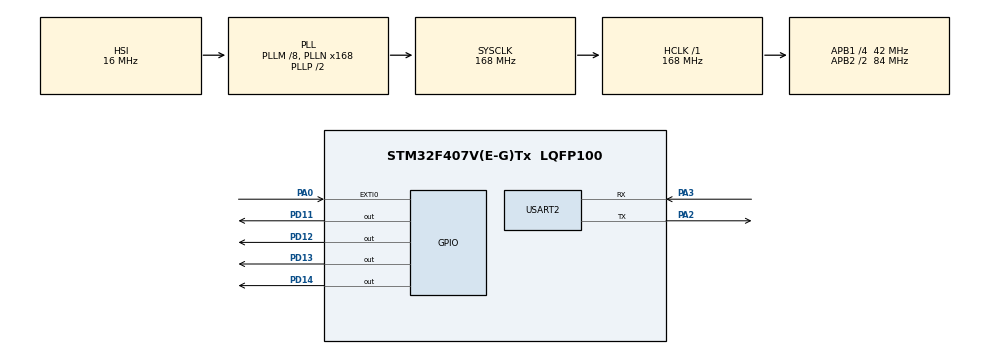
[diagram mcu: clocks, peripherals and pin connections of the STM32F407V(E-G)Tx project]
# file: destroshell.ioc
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Mcu.Family=STM32F4
Mcu.Name=STM32F407V(E-G)Tx
Mcu.Package=LQFP100
NVIC.EXTI0_IRQn=true\:6\:0\:true\:false\:true\:true\:false\:true
NVIC.PriorityGroup=NVIC_PRIORITYGROUP_4
NVIC.TIM6_DAC_IRQn=true\:15\:0\:false\:false\:true\:false\:true\:true
NVIC.TimeBase=TIM6_DAC_IRQn
NVIC.TimeBaseIP=TIM6
NVIC.USART2_IRQn=true\:5\:0\:true\:false\:true\:true\:false\:true
PA0-WKUP.Signal=GPXTI0
PA2.Mode=Asynchronous
PA2.Signal=USART2_TX
PA3.Mode=Asynchronous
PA3.Signal=USART2_RX
PD11.GPIO_Speed=GPIO_SPEED_FREQ_HIGH
PD11.Signal=GPIO_Output
PD12.GPIO_Speed=GPIO_SPEED_FREQ_HIGH
PD12.Signal=GPIO_Output
PD13.GPIO_Speed=GPIO_SPEED_FREQ_HIGH
PD13.Signal=GPIO_Output
PD14.GPIO_Speed=GPIO_SPEED_FREQ_HIGH
PD14.Signal=GPIO_Output
ProjectManager.HeapSize=0x200
ProjectManager.StackSize=0x400
ProjectManager.TargetToolchain=STM32CubeIDE
RCC.48MHZClocksFreq_Value=84000000
RCC.AHBFreq_Value=168000000
RCC.APB1CLKDivider=RCC_HCLK_DIV4
RCC.APB1Freq_Value=42000000
RCC.APB1TimFreq_Value=84000000
RCC.APB2CLKDivider=RCC_HCLK_DIV2
RCC.APB2Freq_Value=84000000
RCC.APB2TimFreq_Value=168000000
RCC.CortexFreq_Value=168000000
RCC.HCLKFreq_Value=168000000
RCC.HSE_VALUE=25000000
RCC.HSI_VALUE=16000000
RCC.LSE_VALUE=32768
RCC.PLLM=8
RCC.PLLN=168
RCC.SYSCLKFreq_VALUE=168000000
RCC.SYSCLKSource=RCC_SYSCLKSOURCE_PLLCLK
RCC.VCOOutputFreq_Value=336000000
USART2.VirtualMode=VM_ASYNC
VP_SYS_VS_tim6.Mode=TIM6
board=custom

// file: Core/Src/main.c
/* USER CODE BEGIN Header */
/**
  ******************************************************************************
  * @file           : main.c
  * @brief          : Main program body
  ******************************************************************************
  * @attention
  *
  * Copyright (c) 2024 STMicroelectronics.
  * All rights reserved.
  *
  * This software is licensed under terms that can be found in the LICENSE file
  * in the root directory of this software component.
  * If no LICENSE file comes with this software, it is provided AS-IS.
  *
  ******************************************************************************
  */
/* USER CODE END Header */
#include "main.h"

/* USER CODE BEGIN Includes */
#include <FreeRTOS.h>
#include <task.h>
#include <queue.h>
/* USER CODE END Includes */

/* USER CODE BEGIN PD */
#define DWT_CTRL    (*(volatile uint32_t*)0xE0001000)
/* USER CODE END PD */

UART_HandleTypeDef shellUSART;

/* USER CODE BEGIN PV */
Shell_Handle_t shellHandle;
/* USER CODE END PV */

void SystemClock_Config(void);
static void MX_GPIO_Init(void);
static void MX_USART2_UART_Init(void);

int main(void)
{

  /* MCU Configuration--------------------------------------------------------*/

  /* Reset of all peripherals, Initializes the Flash interface and the Systick. */
  HAL_Init();

  /* Configure the system clock */
  SystemClock_Config();

  /* Initialize all configured peripherals */
  MX_GPIO_Init();
  MX_USART2_UART_Init();
  /* USER CODE BEGIN 2 */

  //CYCLCNT enable
  DWT_CTRL |= ( 1 << 0);

  SEGGER_SYSVIEW_Conf();

  /* Initialize shell */
  Shell_Init(&shellHandle, &shellUSART);

  /* Create shell task */
  xTaskCreate(Shell_Task, "Shell", 512, &shellHandle, 1, NULL);
  xTaskCreate(vUartTask, "UART", 512, &shellHandle, 1, NULL);

  Shell_RegisterCommand("clear", "Clear the terminal screen", "clear", shell_cmd_clear);
  Shell_RegisterCommand("help", "Display help information for commands", "help [command]", shell_cmd_help);
  Shell_RegisterCommand("status", "Show system status information", "status", shell_cmd_status);
  Shell_RegisterCommand("reset", "Reset the system", "reset", shell_cmd_reset);
  Shell_RegisterCommand("cancel", "Cancel pending reset", "cancel reset", shell_cmd_reset_cancel);
  Shell_RegisterCommand("pin", "Control GPIO pins", "pin <set/reset/read/toggle> <port: A, B, etc.> <pin_number>", shell_cmd_pin);
  Shell_RegisterCommand("tasks", "Manage system tasks", "tasks list | tasks info <task_name>", shell_cmd_tasks);
  Shell_RegisterCommand("heap", "Show heap memory information", "heap", shell_cmd_heap);
  Shell_RegisterCommand("stack", "Show stack usage for all tasks", "stack", shell_cmd_stack);
  Shell_RegisterCommand("init", "Initialize peripheral", "init", shell_cmd_init);

  //start the freeRTOS scheduler
  vTaskStartScheduler();
  /* USER CODE END 2 */

  /* Infinite loop */
  while (1)
  {

  }
}

void SystemClock_Config(void)
{
  RCC_OscInitTypeDef RCC_OscInitStruct = {0};
  RCC_ClkInitTypeDef RCC_ClkInitStruct = {0};

  /** Configure the main internal regulator output voltage
  */
  __HAL_RCC_PWR_CLK_ENABLE();
  __HAL_PWR_VOLTAGESCALING_CONFIG(PWR_REGULATOR_VOLTAGE_SCALE1);

  /** Initializes the RCC Oscillators according to the specified parameters
  * in the RCC_OscInitTypeDef structure.
  */
  RCC_OscInitStruct.OscillatorType = RCC_OSCILLATORTYPE_HSI;
  RCC_OscInitStruct.HSIState = RCC_HSI_ON;
  RCC_OscInitStruct.HSICalibrationValue = RCC_HSICALIBRATION_DEFAULT;
  RCC_OscInitStruct.PLL.PLLState = RCC_PLL_ON;
  RCC_OscInitStruct.PLL.PLLSource = RCC_PLLSOURCE_HSI;
  RCC_OscInitStruct.PLL.PLLM = 8;
  RCC_OscInitStruct.PLL.PLLN = 168;
  RCC_OscInitStruct.PLL.PLLP = RCC_PLLP_DIV2;
  RCC_OscInitStruct.PLL.PLLQ = 4;
  if (HAL_RCC_OscConfig(&RCC_OscInitStruct) != HAL_OK)
  {
    Error_Handler();
  }

  /** Initializes the CPU, AHB and APB buses clocks
  */
  RCC_ClkInitStruct.ClockType = RCC_CLOCKTYPE_HCLK|RCC_CLOCKTYPE_SYSCLK
                              |RCC_CLOCKTYPE_PCLK1|RCC_CLOCKTYPE_PCLK2;
  RCC_ClkInitStruct.SYSCLKSource = RCC_SYSCLKSOURCE_PLLCLK;
  RCC_ClkInitStruct.AHBCLKDivider = RCC_SYSCLK_DIV1;
  RCC_ClkInitStruct.APB1CLKDivider = RCC_HCLK_DIV4;
  RCC_ClkInitStruct.APB2CLKDivider = RCC_HCLK_DIV2;

  if (HAL_RCC_ClockConfig(&RCC_ClkInitStruct, FLASH_LATENCY_5) != HAL_OK)
  {
    Error_Handler();
  }
}

static void MX_USART2_UART_Init(void)
{

  shellUSART.Instance = USART2;
  shellUSART.Init.BaudRate = 115200;
  shellUSART.Init.WordLength = UART_WORDLENGTH_8B;
  shellUSART.Init.StopBits = UART_STOPBITS_1;
  shellUSART.Init.Parity = UART_PARITY_NONE;
  shellUSART.Init.Mode = UART_MODE_TX_RX;
  shellUSART.Init.HwFlowCtl = UART_HWCONTROL_NONE;
  shellUSART.Init.OverSampling = UART_OVERSAMPLING_16;
  if (HAL_UART_Init(&shellUSART) != HAL_OK)
  {
    Error_Handler();
  }
  /* USER CODE BEGIN USART2_Init 2 */
  __HAL_UART_ENABLE_IT(&shellUSART, UART_IT_ERR);
  __HAL_UART_ENABLE_IT(&shellUSART, UART_IT_RXNE);
  /* USER CODE END USART2_Init 2 */

}

static void MX_GPIO_Init(void)
{
  GPIO_InitTypeDef GPIO_InitStruct = {0};

  /* GPIO Ports Clock Enable */
  __HAL_RCC_GPIOA_CLK_ENABLE();
  __HAL_RCC_GPIOD_CLK_ENABLE();

  /*Configure GPIO pin Output Level */
  HAL_GPIO_WritePin(GPIOD, GREEN_Pin|ORANGE_Pin|RED_Pin|BLUE_Pin, GPIO_PIN_RESET);

  /*Configure GPIO pin : USR_BTN_Pin */
  GPIO_InitStruct.Pin = USR_BTN_Pin;
  GPIO_InitStruct.Mode = GPIO_MODE_IT_RISING;
  GPIO_InitStruct.Pull = GPIO_NOPULL;
  HAL_GPIO_Init(USR_BTN_GPIO_Port, &GPIO_InitStruct);

  /*Configure GPIO pins : GREEN_Pin ORANGE_Pin RED_Pin BLUE_Pin */
  GPIO_InitStruct.Pin = GREEN_Pin|ORANGE_Pin|RED_Pin|BLUE_Pin;
  GPIO_InitStruct.Mode = GPIO_MODE_OUTPUT_PP;
  GPIO_InitStruct.Pull = GPIO_NOPULL;
  GPIO_InitStruct.Speed = GPIO_SPEED_FREQ_HIGH;
  HAL_GPIO_Init(GPIOD, &GPIO_InitStruct);

  /* EXTI interrupt init*/
  HAL_NVIC_SetPriority(EXTI0_IRQn, 6, 0);
  HAL_NVIC_EnableIRQ(EXTI0_IRQn);

}

void HAL_TIM_PeriodElapsedCallback(TIM_HandleTypeDef *htim)
{
  if (htim->Instance == TIM6) {
    HAL_IncTick();
  }
}

void Error_Handler(void)
{
  __disable_irq();
  while (1)
  {
  }
}
